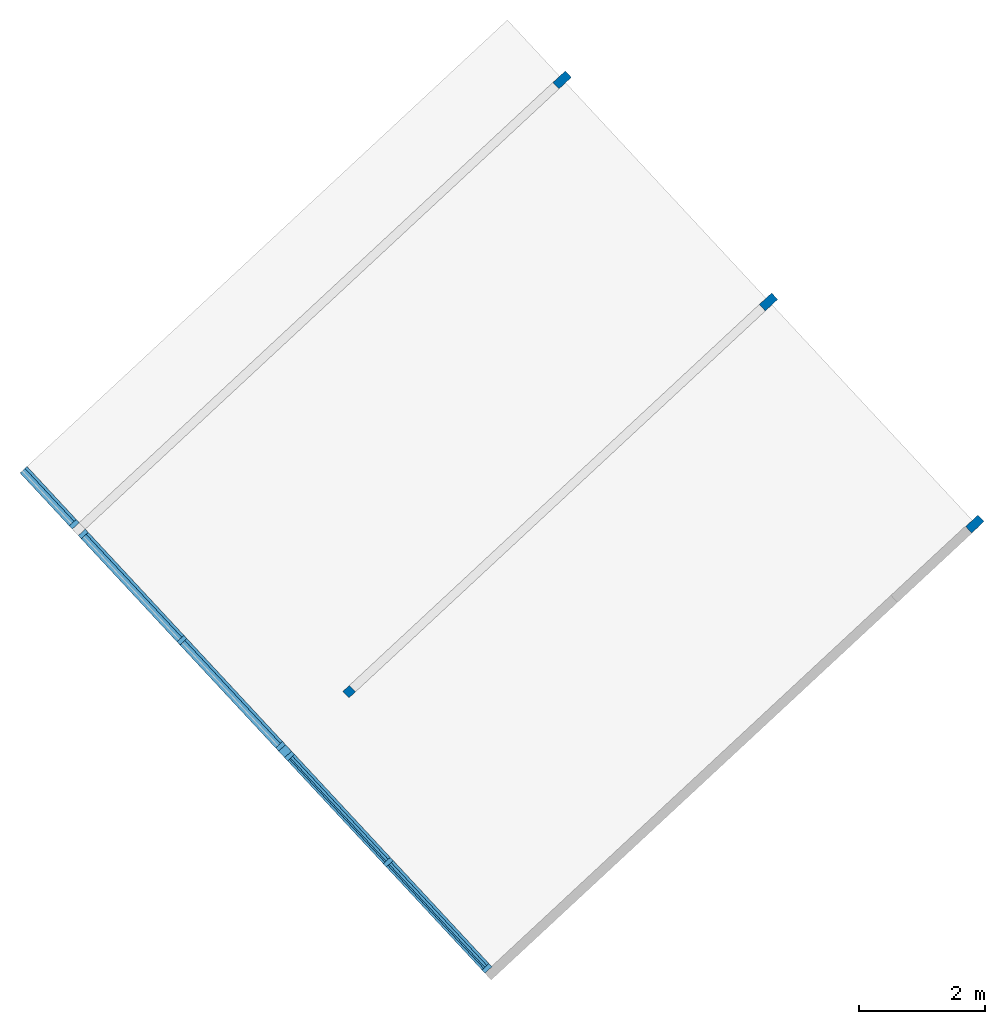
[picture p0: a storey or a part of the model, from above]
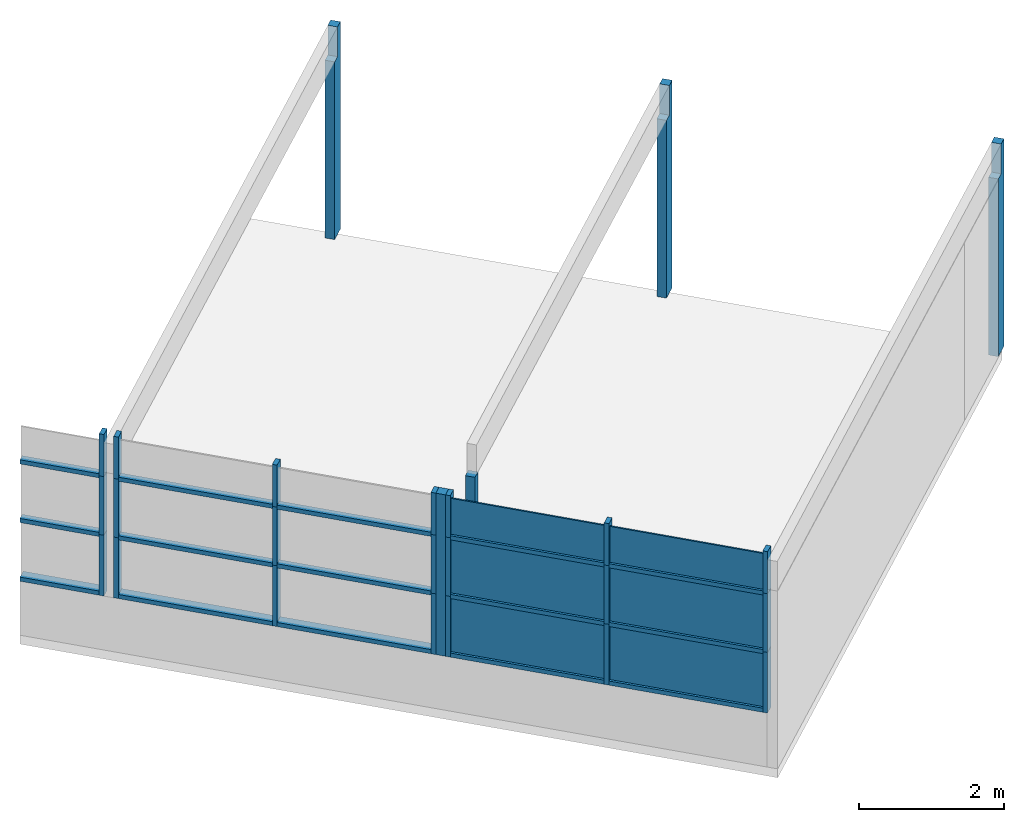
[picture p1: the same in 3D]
Properties of the parts of a building model (IFC2X3)

# File
Description: ViewDefinition [CoordinationView]
File name: ZV002-350-101.1.IFC (Edited by Naviate Simple BIM 2022 version 6)
Time: 2026-03-21T08:07:34+01:00
Written by: ODA SDAI 24.12
Made in: Autodesk Revit 25.4.30.30 (ENU) - IFC 25.4.0.27

# IfcProject, Prosjektnummer
LongName: Prosjektnavn; Phase: Prosjektstatus

# IfcSite, Default
RefLatitude: 59, 54, 57, 599999; RefLongitude: 10, 44, 59, 999999; RefElevation: 0 mm
Other - Project Name: Prosjektnavn; Category: Project Information; Project Status: Prosjektstatus; Project Address: Enter address here; Project Issue Date: Dato; Project Number: Prosjektnummer
Identity Data - Godkjent: AJH; Tiltaket gjelder: Ombygging; Workset: Project Info; Prosjekt: Stavanger lufthavn Sola - Helikopterterminal

# IfcBuilding
Pset_BuildingCommon - NumberOfStoreys: 1
Other - Project Name: Prosjektnavn; Category: Project Information; Project Status: Prosjektstatus; Project Address: Enter address here; Project Issue Date: Dato; Project Number: Prosjektnummer
Identity Data - Godkjent: AJH; Tiltaket gjelder: Ombygging; Workset: Project Info; Prosjekt: Stavanger lufthavn Sola - Helikopterterminal

# IfcBuildingStorey: Level:Nivå 2.5mm, 001-01
LongName: 001-01; Elevation: 4900 mm
Identity Data - Structural: no; Building Story: yes; Name: 001-01; Workset: Shared Levels and Grids
Pset_AirSideSystemInformation - Name: 001-01; sets with these values: 2
Other - Type: Nivå 2.5mm; Family and Type: Level: Nivå 2.5mm; Type Id: 305; Category: Levels; Family: Level
Graphics(Type) - Line Pattern: Centre; Color: 0; Symbol at End 1 Default: no; Symbol at End 2 Default: yes; Line Weight: 1; Symbol: Nivåhode : Nivåhode Trekant
Identity Data(Type) - Workset: Level Types; Type Name: Nivå 2.5mm
Constraints - Elevation: 4900 mm
Constraints(Type) - Elevation Base: Project Base Point
Other(Type) - Category: Levels; Family Name: Level
Dimensions - Computation Height: 1200 mm

# IfcBuildingElementProxy: 933*140 48456:933*140 48456 (2)
In: 001-01
Type - Material: TIMBER/C24
Type - Other - Category: Structural Framing; Family Name: 933*140 48456
Type - Identity Data - Type Name: 933*140 48456; Workset: Family : Structural Framing : 933*140 48456
Type - Materials and Finishes - Material: TIMBER/C24
Type - Structural - Section Shape: 0
Pset_BuildingElementProxyCommon - Reference: 933*140 48456; sets with these values: 2
Phasing - Phase Created: Final
ePset_LocationTool - Splitting: RESULT
Constraints - Host: Level : 001-01; Moves With Nearby Elements: no; Level: 001-01
Other - Type Id: 785722; Family and Type: 933*140 48456: 933*140 48456; Family: 933*140 48456; Type: 933*140 48456
ePset_SimplebimBasicQuantities - Volume, net (Simplebim): 0.73717 m3; Thickness (Simplebim): 140 mm; Height (Simplebim): 499 mm; Length (Simplebim): 10531 mm; Area, largest surface, net (Simplebim): 5.2655 m2
Structural - Rebar Cover - Top Face: Rebar Cover 1 <25 mm>; Rebar Cover - Other Faces: Rebar Cover 1 <25 mm>; Rebar Cover - Bottom Face: Rebar Cover 1 <25 mm>
Identity Data - Workset: Workset1
ePset_Simplebim - Assembly Level: Leaf
Group: Model Group:RIB_søyler_Eksisterende:1148207
Name (933*140 48456:933*140 48456:...)
1148320
1148321

# IfcBuildingElementProxy: 933*140 49506:933*140 49506, 933*140 49506:933*140 49506:1148334
In: 001-01
Type - Material: TIMBER/C24
Type - Other - Category: Structural Framing; Family Name: 933*140 49506
Type - Identity Data - Type Name: 933*140 49506; Workset: Family : Structural Framing : 933*140 49506
Type - Materials and Finishes - Material: TIMBER/C24
Type - Structural - Section Shape: 0
ePset_LocationTool - Splitting: RESULT
Phasing - Phase Created: Final
ePset_SimplebimBasicQuantities - Volume, net (Simplebim): 0.6349 m3; Thickness (Simplebim): 140 mm; Height (Simplebim): 499 mm; Length (Simplebim): 9070 mm; Area, largest surface, net (Simplebim): 4.535 m2
Other - Family and Type: 933*140 49506: 933*140 49506; Type: 933*140 49506; Family: 933*140 49506; Type Id: 785726
Constraints - Host: Level : 001-01; Moves With Nearby Elements: no; Level: 001-01
Pset_QuantityTakeOff - Reference: 933*140 49506; sets with these values: 2
Structural - Rebar Cover - Top Face: Rebar Cover 1 <25 mm>; Rebar Cover - Other Faces: Rebar Cover 1 <25 mm>; Rebar Cover - Bottom Face: Rebar Cover 1 <25 mm>
Identity Data - Workset: Workset1
ePset_Simplebim - Assembly Level: Leaf
Group: Model Group:RIB_søyler_Eksisterende:1148207

# IfcColumn: 140*140:140*140, 140*140:140*140:1148728
In: 001-01
Type - PredefinedType: COLUMN; Material: TIMBER/C30
Type - Other - Category: Columns; Family Name: 140*140
Type - Graphics - Coarse Scale Fill Color: 0
Type - Identity Data - Type Name: 140*140; Workset: Family : Columns : 140*140
Type - Materials and Finishes - Material: TIMBER/C30
Dimensions - Volume: 0.0588 m3
Pset_ColumnCommon - IsExternal: no; Slope: 0 deg; Reference: 140*140
Constraints - Base Offset: 0 mm; Room Bounding: yes; Moves With Grids: yes; Top Offset: 3000 mm; Level: 001-01; Base Level: 001-01; Top Level: 001-01
ePset_SimplebimBasicQuantities - Volume, net (Simplebim): 0.0588 m3; Width (Simplebim): 140 mm; Area, sides, net (Simplebim): 1.68 m2; Weight, as steel (Simplebim): 461.58 kg; Depth (Simplebim): 140 mm; Height (Simplebim): 3000 mm
Identity Data - Workset: Workset1
Pset_ProductRequirements - Name: Tresøyle
ePset_LocationTool - Splitting: ORIGINAL
Phasing - Phase Created: Final
ePset_Simplebim - Assembly Level: Leaf
Other - Type Id: 785714; Family: 140*140; Type: 140*140; Family and Type: 140*140: 140*140
Pset_QuantityTakeOff - Reference: 140*140; sets with these values: 2
Group: Model Group:RIB_søyler_Eksisterende:1148207

# IfcColumn: 267*140 51453:267*140 51453 (3)
In: 001-01
Type - PredefinedType: COLUMN; Material: TIMBER/C30
Type - Other - Category: Columns; Family Name: 267*140 51453
Type - Graphics - Coarse Scale Fill Color: 0
Type - Identity Data - Type Name: 267*140 51453; Workset: Family : Columns : 267*140 51453
Type - Materials and Finishes - Material: TIMBER/C30
Constraints - Room Bounding: yes; Moves With Grids: yes; Level: 001-01; Base Level: 001-01; Top Level: 001-01
ePset_SimplebimBasicQuantities - Area, sides, net (Simplebim): 2.7155 m2; Volume, net (Simplebim): 0.121485 m3; Width (Simplebim): 140 mm; Depth (Simplebim): 267 mm; Height (Simplebim): 3500 mm; Weight, as steel (Simplebim): 953.657 kg
Pset_ReinforcementBarPitchOfColumn - Reference: 267*140 51453; sets with these values: 2
Other - Type Id: 785730; Family: 267*140 51453; Type: 267*140 51453; Family and Type: 267*140 51453: 267*140 51453
ePset_LocationTool - Splitting: RESULT
Identity Data - Workset: Workset1
Pset_ProductRequirements - Name: Tresøyle
Phasing - Phase Created: Final
ePset_Simplebim - Assembly Level: Leaf
Pset_ColumnCommon - Reference: 267*140 51453; IsExternal: no
Group: Model Group:RIB_søyler_Eksisterende:1148207
Name (267*140 51453:267*140 51453:...)
1148747
1148749
1148751

# IfcCurtainWall: Curtain Wall:Curtain Wall 1, Curtain Wall:Curtain Wall 1:1253499
In: 001-01
Type - Other - Category: Walls; Family Name: Curtain Wall
Type - Construction - Function: Interior; Automatically Embed: yes; Join Condition: Not Defined
Type - Identity Data - Type Name: Curtain Wall 1; Workset: Curtain Wall Types
Type - Horizontal Grid - Adjust for Mullion Size: no
Type - Vertical Grid - Adjust for Mullion Size: no
Cross-Section Definition - Cross-Section: Vertical
Pset_QuantityTakeOff - Reference: Curtain Wall 1
Other - Family and Type: Curtain Wall: Curtain Wall 1; Type: Curtain Wall 1; Type Id: 206834; Family: Curtain Wall
ePset_LocationTool - Splitting: ORIGINAL
Structural - Structural Usage: Non-bearing; Structural: no
Pset_CurtainWallCommon - IsExternal: no; Reference: Curtain Wall 1
Phasing - Phase Created: Fase 3
Identity Data - Comments: 6 x IV4; Mark: GV - H1800; Workset: Workset1
Constraints - Base is Attached: no; Related to Mass: no; Room Bounding: yes; Top is Attached: no; Top Constraint: Up to level: 001-02; Top Offset: 385 mm; Base Offset: 910 mm; Unconnected Height: 2725 mm; Base Constraint: 001-01
ePset_Simplebim - Assembly Level: Topmost
ePset_SimplebimBasicQuantities - Length: 28660 mm; Volume, net (Simplebim): 3.33304 m3; Width: 150 mm; Height: 2725 mm
Dimensions - Area: 77.7429 m2; Length: 28730 mm
Horizontal Grid - Number: 4; Angle: 0 deg; Offset: 0 mm; Justification: Beginning
Vertical Grid - Angle: 0 deg; Offset: 0 mm; Number: 4; Justification: Beginning

# IfcGroup: Model Group:RIB_søyler_Eksisterende, Model Group:RIB_søyler_Eksisterende:1148207
Other - Category: Model Groups; Family and Type: Model Group: RIB_søyler_Eksisterende; Family: Model Group; Type Id: 767239; Type: RIB_søyler_Eksisterende
Identity Data(Type) - Type Name: RIB_søyler_Eksisterende; Workset: Workset1
Constraints - Origin Level Offset: 0 mm; Reference Level: 001-01
Identity Data - Workset: Workset1
Other(Type) - Category: Model Groups; Family Name: Model Group

# IfcMember: Rectangular Mullion:70x105mm Aluminium (10)
In: 001-01
Type - PredefinedType: MULLION; Material: Aluminium
Type - Other - Category: Curtain Wall Mullions; Family Name: Rectangular Mullion
Type - Constraints - Angle: 0 deg; Offset: 22.5 mm
Type - Construction - Corner Mullion: no; Position: Perpendicular to Face; Profile: System Mullion Profile: Rectangular; Thickness: 105 mm
Type - Dimensions - Width on side 1: 35 mm; Width on side 2: 35 mm
Type - Identity Data - Type Name: 70x105mm Aluminium; Workset: Family : Curtain Wall Mullions : Rectangular Mullion
Type - Materials and Finishes - Material: Aluminium
Constraints - Level: 001-01
Phasing - Phase Created: Fase 3
Pset_MemberCommon - Reference: 70x105mm Aluminium; IsExternal: no
Identity Data - Workset: Workset1
Other - Type Id: 1250423; Family: Rectangular Mullion; Host Id: 1253499; Type: 70x105mm Aluminium; Family and Type: Rectangular Mullion: 70x105mm Aluminium
ePset_Simplebim - Assembly Level: Leaf
Pset_QuantityTakeOff - Reference: 70x105mm Aluminium
ePset_SimplebimBasicQuantities - Height (Simplebim): 70 mm; Width (Simplebim): 105 mm
Name (Rectangular Mullion:70x105mm Aluminium:...) | Volume (m3) | Length (mm) = Span (mm) | Area (m2) | Splitting | Weight, as steel (Simplebim) (kg) | Volume, net (Simplebim) (m3) | Length (Simplebim) (mm) | Area, sides, net (Simplebim) (m2)
723658 | 0.0163538 | 2225 | 0.396725 | ORIGINAL | 128.377 | 0.0163538 | 2225 | 0.79345
723669 | 0.0163538 | 2225 | 0.396725 | ORIGINAL | 128.377 | 0.0163538 | 2225 | 0.79345
1253491 | 0.0163538 | 2225 | 0.396725 | ORIGINAL | 128.377 | 0.0163538 | 2225 | 0.79345
1253676 | 0.0163538 | 2225 | 0.396725 | ORIGINAL | 128.377 | 0.0163538 | 2225 | 0.79345
1261940 | 0.0163538 | 2225 | 0.396725 | ORIGINAL | 128.377 | 0.0163538 | 2225 | 0.79345
1261941 | 0.0163538 | 2225 | 0.396725 | ORIGINAL | 128.377 | 0.0163538 | 2225 | 0.79345
1261942 | 0.0163538 | 2225 | 0.396725 | ORIGINAL | 128.377 | 0.0163538 | 2225 | 0.79345
1261943 | 0.0163538 | 2225 | 0.396725 | ORIGINAL | 128.377 | 0.0163538 | 2225 | 0.79345
1261944 |  |  |  | RESULT | 66.0558 | 0.00841475 | 1145 | 0.415402
723667 |  |  |  | RESULT | 66.0558 | 0.00841475 | 1145 | 0.415402

# IfcMember: Rectangular Mullion:70x150mm Aluminium (26)
In: 001-01
Type - PredefinedType: MULLION; Material: Aluminium
Type - Other - Category: Curtain Wall Mullions; Family Name: Rectangular Mullion
Type - Constraints - Angle: 0 deg; Offset: 0 mm
Type - Construction - Corner Mullion: no; Position: Perpendicular to Face; Profile: System Mullion Profile: Rectangular; Thickness: 150 mm
Type - Dimensions - Width on side 1: 35 mm; Width on side 2: 35 mm
Type - Identity Data - Type Name: 70x150mm Aluminium; Workset: Family : Curtain Wall Mullions : Rectangular Mullion
Type - Materials and Finishes - Material: Aluminium
Constraints - Level: 001-01
Other - Family: Rectangular Mullion; Host Id: 1253499; Type: 70x150mm Aluminium; Type Id: 1249671; Family and Type: Rectangular Mullion: 70x150mm Aluminium
Phasing - Phase Created: Fase 3
Pset_MemberCommon - Reference: 70x150mm Aluminium; IsExternal: no
Identity Data - Workset: Workset1
ePset_Simplebim - Assembly Level: Leaf
Pset_QuantityTakeOff - Reference: 70x150mm Aluminium
Name (Rectangular Mullion:70x150mm Aluminium:...) | Splitting | Length (mm) = Span (mm) | Area (m2) | Volume (m3) | Height (Simplebim) (mm) | Length (Simplebim) (mm) | Weight, as steel (Simplebim) (kg) | Width (Simplebim) (mm) | Area, sides, net (Simplebim) (m2) | Volume, net (Simplebim) (m3)
345215 | ORIGINAL | 1025 | 0.236 | 0.0107625 | 1025 | 150 | 84.4856 | 70 | 0.472 | 0.0107625
345221 | ORIGINAL | 1025 | 0.236 | 0.0107625 | 1025 | 150 | 84.4856 | 70 | 0.472 | 0.0107625
345222 | ORIGINAL | 1025 | 0.236 | 0.0107625 | 1025 | 150 | 84.4856 | 70 | 0.472 | 0.0107625
345223 | ORIGINAL | 1025 | 0.236 | 0.0107625 | 1025 | 150 | 84.4856 | 70 | 0.472 | 0.0107625
345237 | ORIGINAL | 2225 | 0.5 | 0.0233625 | 70 | 2225 | 183.396 | 150 | 1 | 0.0233625
723165 | ORIGINAL | 990 | 0.2283 | 0.010395 | 990 | 150 | 81.6008 | 70 | 0.4566 | 0.010395
723169 | ORIGINAL | 990 | 0.2283 | 0.010395 | 990 | 150 | 81.6008 | 70 | 0.4566 | 0.010395
723170 | ORIGINAL | 990 | 0.2283 | 0.010395 | 990 | 150 | 81.6008 | 70 | 0.4566 | 0.010395
723171 | ORIGINAL | 990 | 0.2283 | 0.010395 | 990 | 150 | 81.6008 | 70 | 0.4566 | 0.010395
723567 | ORIGINAL | 2225 | 0.5 | 0.0233625 | 70 | 2225 | 183.396 | 150 | 1 | 0.0233625
723652 | ORIGINAL | 1025 | 0.236 | 0.0107625 | 1025 | 150 | 84.4856 | 70 | 0.472 | 0.0107625
723672 | ORIGINAL | 990 | 0.2283 | 0.010395 | 990 | 150 | 81.6008 | 70 | 0.4566 | 0.010395
1253489 | ORIGINAL | 2225 | 0.5 | 0.0233625 | 70 | 2225 | 183.396 | 150 | 1 | 0.0233625
1253620 | ORIGINAL | 710 | 0.1667 | 0.007455 | 710 | 150 | 58.5217 | 70 | 0.3334 | 0.007455
1253621 | ORIGINAL | 1025 | 0.236 | 0.0107625 | 1025 | 150 | 84.4856 | 70 | 0.472 | 0.0107625
1253675 | ORIGINAL | 2225 | 0.5 | 0.0233625 | 70 | 2225 | 183.396 | 150 | 1 | 0.0233625
1253717 | ORIGINAL | 1025 | 0.236 | 0.0107625 | 1025 | 150 | 84.4856 | 70 | 0.472 | 0.0107625
1253718 | ORIGINAL | 990 | 0.2283 | 0.010395 | 990 | 150 | 81.6008 | 70 | 0.4566 | 0.010395
1261836 | ORIGINAL | 710 | 0.1667 | 0.007455 | 710 | 150 | 58.5217 | 70 | 0.3334 | 0.007455
1261840 | ORIGINAL | 710 | 0.1667 | 0.007455 | 710 | 150 | 58.5217 | 70 | 0.3334 | 0.007455
1261841 | ORIGINAL | 710 | 0.1667 | 0.007455 | 710 | 150 | 58.5217 | 70 | 0.3334 | 0.007455
1261842 | ORIGINAL | 710 | 0.1667 | 0.007455 | 710 | 150 | 58.5217 | 70 | 0.3334 | 0.007455
1261844 | ORIGINAL | 710 | 0.1667 | 0.007455 | 710 | 150 | 58.5217 | 70 | 0.3334 | 0.007455
1261850 | ORIGINAL | 990 | 0.2283 | 0.010395 | 990 | 150 | 81.6008 | 70 | 0.4566 | 0.010395
1261851 | ORIGINAL | 710 | 0.1667 | 0.007455 | 710 | 150 | 58.5217 | 70 | 0.3334 | 0.007455
345235 | RESULT |  |  |  | 70 | 1145 | 94.3654 | 150 | 0.52474 | 0.0120211

# IfcPlate: System Panel:Glassfelt 25mm (15)
In: 001-01
Type - PredefinedType: CURTAIN_PANEL; Material: Glass
Type - Other - Category: Curtain Panels; Family Name: System Panel
Type - Constraints - Offset: 25 mm
Type - Dimensions - Thickness: 25 mm
Type - Identity Data - Type Name: Glassfelt 25mm; Workset: Family : Curtain Panels : System Panel
Type - Materials and Finishes - Material: Glass
Type - Analytical Properties - Define Thermal Properties by: Schematic Type; Analytic Construction: <None>
Other - Host Id: 1253499; Type Id: 12611; Family and Type: System Panel: Glassfelt 25mm; Type: Glassfelt 25mm; Family: System Panel
Constraints - Level: 001-01
Identity Data - Workset: Workset1
Phasing - Phase Created: Fase 3
Pset_QuantityTakeOff - Reference: Glassfelt 25mm
ePset_Simplebim - Assembly Level: Leaf
Pset_PlateCommon - IsExternal: no; Reference: Glassfelt 25mm
Name (System Panel:Glassfelt 25mm:...) | Area, largest surface, net (Simplebim) (m2) | Volume, net (Simplebim) (m3) | Weight, as steel (Simplebim) (kg) | Area (m2) | Volume (m3) | Height (mm) | Width (mm) | Splitting
1253480 | 2.047 | 0.051175 | 401.724 | 2.047 | 0.051175 | 920 | 2225 | ORIGINAL
1253662 | 2.047 | 0.051175 | 401.724 | 2.047 | 0.051175 | 920 | 2225 | ORIGINAL
344761 | 2.047 | 0.051175 | 401.724 | 2.047 | 0.051175 | 920 | 2225 | ORIGINAL
723563 | 2.047 | 0.051175 | 401.724 | 2.047 | 0.051175 | 920 | 2225 | ORIGINAL
1253481 | 2.047 | 0.051175 | 401.724 | 2.047 | 0.051175 | 920 | 2225 | ORIGINAL
1253663 | 2.047 | 0.051175 | 401.724 | 2.047 | 0.051175 | 920 | 2225 | ORIGINAL
723142 | 2.047 | 0.051175 | 401.724 | 2.047 | 0.051175 | 920 | 2225 | ORIGINAL
723564 | 2.047 | 0.051175 | 401.724 | 2.047 | 0.051175 | 920 | 2225 | ORIGINAL
1261802 | 1.34613 | 0.0336531 | 264.177 | 1.34613 | 0.0336531 | 605 | 2225 | ORIGINAL
1261803 | 1.34613 | 0.0336531 | 264.177 | 1.34613 | 0.0336531 | 605 | 2225 | ORIGINAL
1261805 | 1.34613 | 0.0336531 | 264.177 | 1.34613 | 0.0336531 | 605 | 2225 | ORIGINAL
1261806 | 1.34613 | 0.0336531 | 264.177 | 1.34613 | 0.0336531 | 605 | 2225 | ORIGINAL
1261808 | 0.618226 | 0.0154557 | 121.327 |  |  |  |  | RESULT
723144 | 1.05327 | 0.0263319 | 206.705 |  |  |  |  | RESULT
344813 | 1.05327 | 0.0263319 | 206.705 |  |  |  |  | RESULT

# IfcPlate: System Panel:Tettfelt 150mm (2)
In: 001-01
Type - PredefinedType: CURTAIN_PANEL; Material: Aluminium
Type - Other - Category: Curtain Panels; Family Name: System Panel
Type - Constraints - Offset: 0 mm
Type - Dimensions - Thickness: 150 mm
Type - Identity Data - Type Name: Tettfelt 150mm; Workset: Family : Curtain Panels : System Panel
Type - Materials and Finishes - Material: Aluminium
Type - Analytical Properties - Define Thermal Properties by: Schematic Type; Analytic Construction: <None>
Constraints - Level: 001-01
Other - Family and Type: System Panel: Tettfelt 150mm; Type Id: 687138; Host Id: 1253499; Type: Tettfelt 150mm; Family: System Panel
Identity Data - Workset: Workset1
Phasing - Phase Created: Fase 3
Pset_QuantityTakeOff - Reference: Tettfelt 150mm
ePset_LocationTool - Splitting: ORIGINAL
ePset_Simplebim - Assembly Level: Leaf
Pset_PlateCommon - IsExternal: no; Reference: Tettfelt 150mm
Name (System Panel:Tettfelt 150mm:...) | Weight, as steel (Simplebim) (kg) | Area, largest surface, net (Simplebim) (m2) | Volume, net (Simplebim) (m3) = Volume (m3) | Area (m2) | Width (mm) | Height (mm)
344740 | 449.216 | 0.40875 | 0.057225 | 0.3815 | 140 | 2725
344794 | 344.537 | 0.3135 | 0.04389 | 0.292601 | 140.001 | 2090

# IfcSlab: Floor:Betong Plasstøpt 150mm, Floor:Betong Plasstøpt 150mm:653308
In: 001-01
Type - PredefinedType: FLOOR; Material: Betong - Plasstøpt 150 mm
Type - Other - Category: Floors; Family Name: Floor
Type - Construction - Function: Interior; Default Thickness: 150 mm
Type - Graphics - Coarse Scale Fill Color: 0
Type - Identity Data - Type Name: Betong Plasstøpt 150mm; Workset: Floor Types
Type - Materials and Finishes - Structural Material: Betong - Plasstøpt
Type - Analytical Properties - Absorptance: 0.1; Roughness: 1
Identity Data - Has Association: no; Workset: Workset1
Pset_ReinforcementBarPitchOfSlab - Reference: Betong Plasstøpt 150mm; sets with these values: 2
Pset_SlabCommon - Reference: Betong Plasstøpt 150mm; IsExternal: no; LoadBearing: no
Phasing - Phase Created: Fase 5
Structural - Structural: no
ePset_SimplebimBasicQuantities - Area, largest surface, net (Simplebim): 115.495 m2; Area, top, net (Simplebim): 115.495 m2; Perimeter (Simplebim): 42995.8 mm; Area, sides, net (Simplebim): 6.44937 m2; Volume, net (Simplebim): 17.3242 m3; Thickness (Simplebim): 150 mm
Constraints - Related to Mass: no; Room Bounding: yes; Level: 001-01
ePset_Simplebim - Assembly Level: Leaf
ePset_LocationTool - Splitting: RESULT
Other - Type Id: 106384; Family and Type: Floor: Betong Plasstøpt 150mm; Type: Betong Plasstøpt 150mm; Family: Floor

# IfcWall: Basic Wall:Innervegg - 100mm Stender 2+2 Gips (2)
In: 001-01
Type - PredefinedType: STANDARD; Material: Gips 13 mm, Gips 13 mm, Isolasjon 100 mm, Gips 13 mm, Gips 13 mm
Type - Other - Category: Walls; Family Name: Basic Wall
Type - Construction - Function: Interior; Width: 152 mm; Wrapping at Inserts: Do not wrap
Type - Graphics - Coarse Scale Fill Color: 0
Type - Identity Data - Type Name: Innervegg - 100mm Stender 2+2 Gips; Workset: Wall Types
Type - Materials and Finishes - Structural Material: Isolasjon
Type - Analytical Properties - Absorptance: 0.1; Roughness: 1
ePset_SimplebimBasicQuantities - Thickness (Simplebim): 152 mm
Phasing - Phase Created: Fase 3
Structural - Structural Usage: Non-bearing; Structural: no
Cross-Section Definition - Cross-Section: Vertical
Constraints - Base is Attached: no; Related to Mass: no; Room Bounding: yes; Top is Attached: no; Base Constraint: 001-01
ePset_LocationTool - Splitting: RESULT
Pset_WallCommon - IsExternal: no; ExtendToStructure: no; LoadBearing: no; Reference: Innervegg - 100mm Stender 2+2 Gips
Pset_QuantityTakeOff - Reference: Innervegg - 100mm Stender 2+2 Gips; sets with these values: 2
Identity Data - Workset: Workset1
ePset_Simplebim - Assembly Level: Leaf
Other - Family: Basic Wall; Family and Type: Basic Wall: Innervegg - 100mm Stender 2+2 Gips; Type: Innervegg - 100mm Stender 2+2 Gips; Type Id: 1194448
Name (Basic Wall:Innervegg - 100mm Stender 2+2 Gips:...) | Area, side, gross, AABB (Simplebim) (m2) | Volume, net (Simplebim) (m3) | Area, side, gross, average (Simplebim) (m2) = Area, side, gross, smaller (Simplebim) (m2) = Area, side, gross, larger (Simplebim) (m2) | Area, largest surface, net (Simplebim) (m2) = Area, side, net, average (Simplebim) (m2) = Area, side, net, smaller (Simplebim) (m2) = Area, side, net, larger (Simplebim) (m2) | Height (Simplebim) (mm) | Length (Simplebim) (mm) | Location Line
281146 | 9.83801 | 1.49536 | 9.83789 | 9.83789 | 910 | 10811 | Wall Centerline
255625 | 26.352 | 4.0055 | 27.6394 | 26.352 | 3000 | 8784 | Core Face: Interior | Constraints - Top Constraint: Up to level: 001-02

# IfcWallStandardCase: Basic Wall:Innervegg - 100mm Stender 2+2 Gips (eksisterende), Basic Wall:Innervegg - 100mm Stender 2+2 Gips (eksisterende):637850
In: 001-01
Type - PredefinedType: STANDARD; Material: Gips 13 mm, Gips 13 mm, Isolasjon 100 mm, Gips 13 mm, Gips 13 mm
Type - Other - Category: Walls; Family Name: Basic Wall
Type - Construction - Function: Interior; Width: 152 mm; Wrapping at Inserts: Do not wrap
Type - Graphics - Coarse Scale Fill Color: 0
Type - Identity Data - Type Name: Innervegg - 100mm Stender 2+2 Gips (eksisterende); Workset: Wall Types
Type - Materials and Finishes - Structural Material: Isolasjon
Type - Analytical Properties - Absorptance: 0.1; Roughness: 1
ePset_SimplebimBasicQuantities - Volume, net (Simplebim): 0.733476 m3; Area, side, gross, larger (Simplebim): 4.8255 m2; Area, side, gross, smaller (Simplebim): 4.8255 m2; Area, side, net, larger (Simplebim): 4.8255 m2; Area, side, net, average (Simplebim): 4.8255 m2; Area, largest surface, net (Simplebim): 4.8255 m2; Area, side, gross, average (Simplebim): 4.8255 m2; Area, side, net, smaller (Simplebim): 4.8255 m2; Area, side, gross, AABB (Simplebim): 4.8255 m2; Thickness (Simplebim): 152 mm; Length (Simplebim): 1608.5 mm; Height (Simplebim): 3000 mm
Other - Family: Basic Wall; Type Id: 1331656; Type: Innervegg - 100mm Stender 2+2 Gips (eksisterende); Family and Type: Basic Wall: Innervegg - 100mm Stender 2+2 Gips (eksisterende)
Structural - Structural Usage: Non-bearing; Structural: no
ePset_LocationTool - Splitting: ORIGINAL
Cross-Section Definition - Cross-Section: Vertical
Pset_QuantityTakeOff - Reference: Innervegg - 100mm Stender 2+2 Gips (eksisterende); sets with these values: 2
Pset_WallCommon - Reference: Innervegg - 100mm Stender 2+2 Gips (eksisterende); IsExternal: no; ExtendToStructure: no; LoadBearing: no
Dimensions - Volume: 0.733476 m3; Area: 4.8255 m2; Length: 1545.5 mm
Constraints - Location Line: Wall Centerline; Base Extension Distance: 0 mm; Base is Attached: no; Base Offset: 0 mm; Related to Mass: no; Room Bounding: yes; Top Extension Distance: 0 mm; Top is Attached: no; Top Constraint: Up to level: 001-02; Top Offset: -250 mm; Unconnected Height: 3000 mm; Base Constraint: 001-01
Identity Data - Workset: Workset1
Phasing - Phase Created: Eksisterende
ePset_Simplebim - Assembly Level: Leaf
